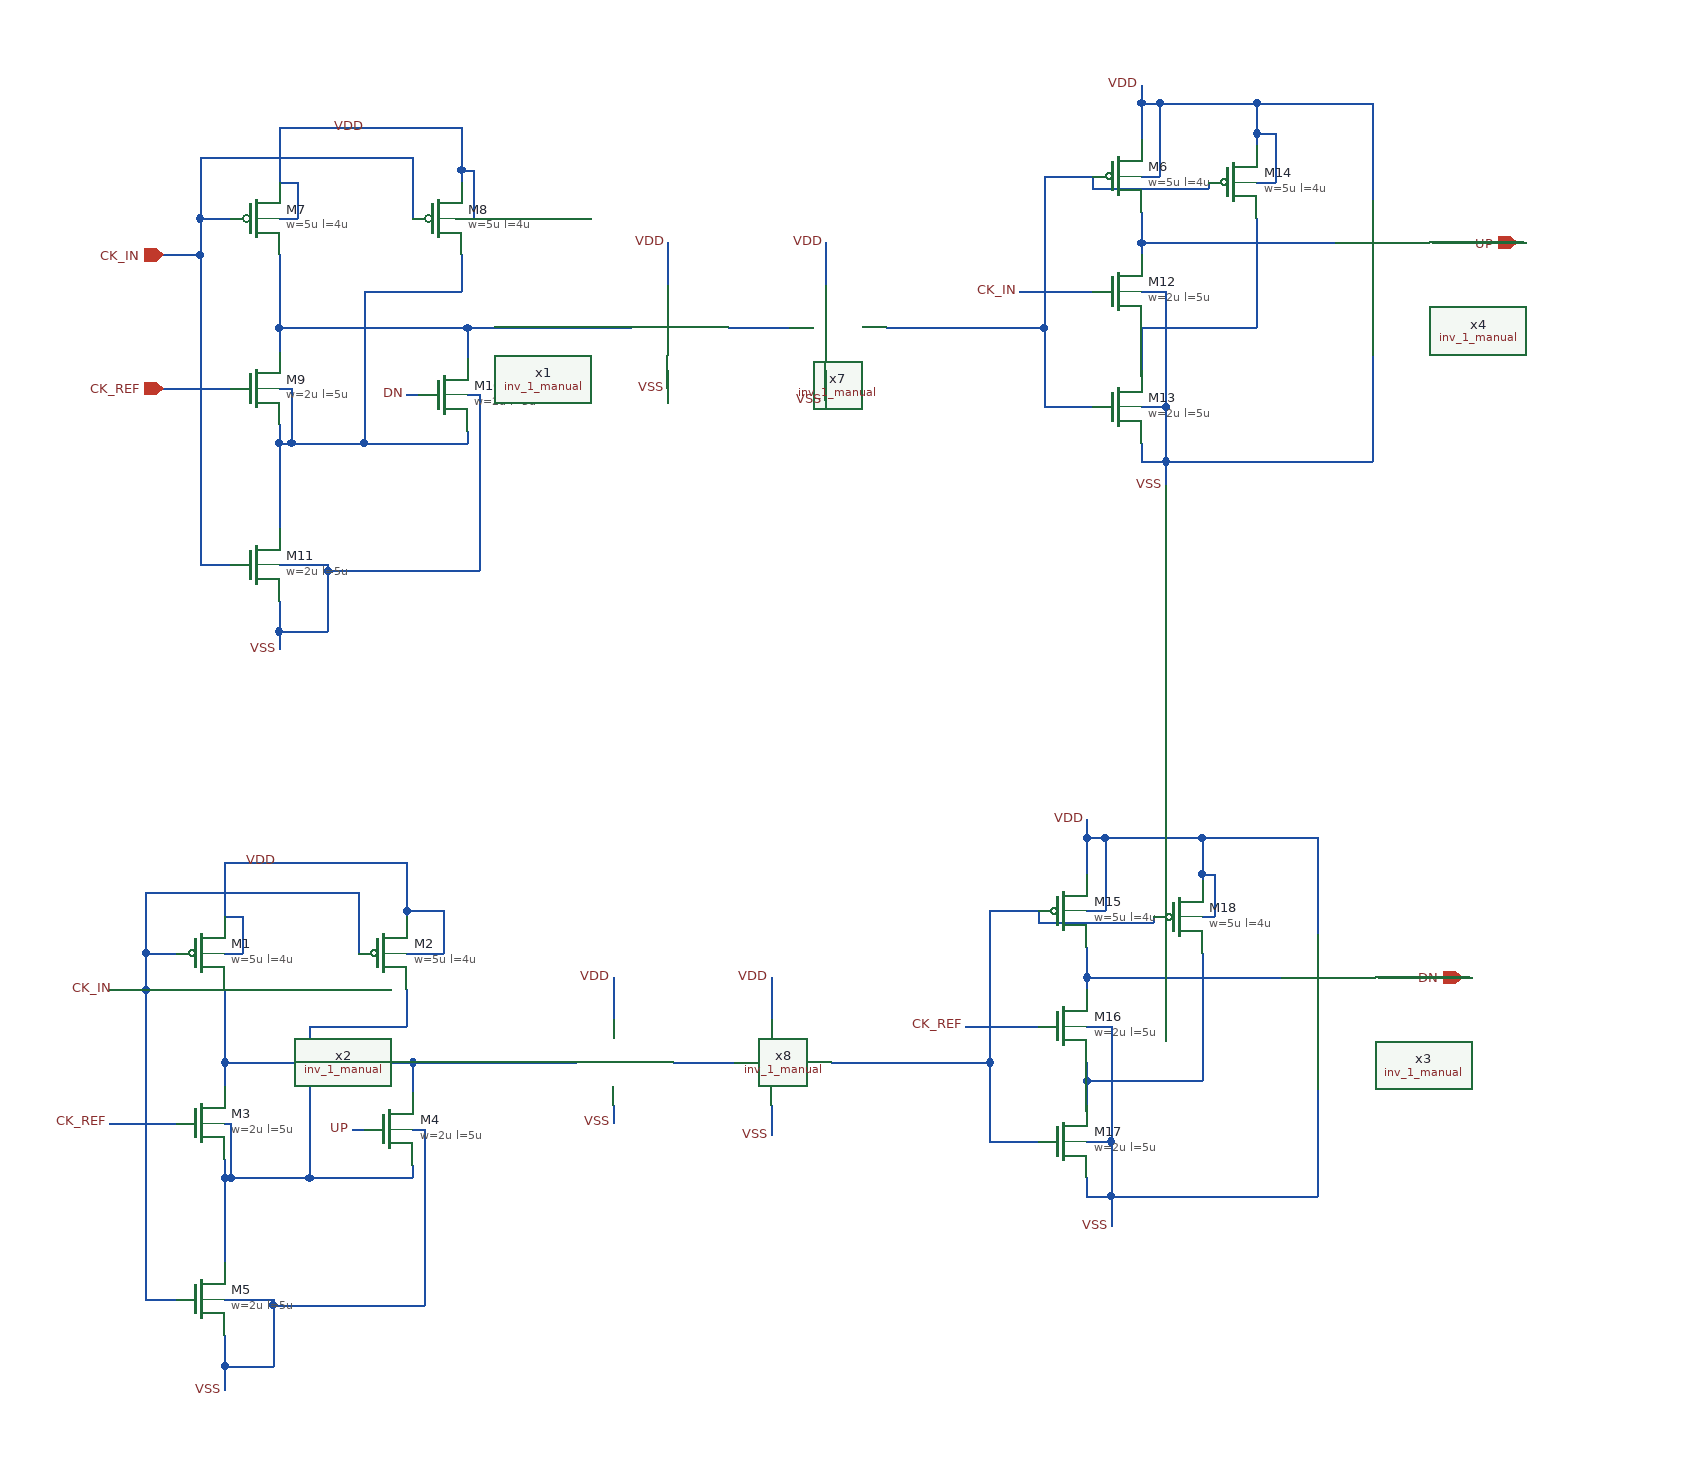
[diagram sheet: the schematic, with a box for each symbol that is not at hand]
v {xschem version=3.4.8RC file_version=1.2}
G {}
K {}
V {}
S {}
F {}
E {}
N 540 85 540 155 {lab=#net1}
N 695 75 695 85 {lab=#net1}
N 540 70 540 85 {lab=#net1}
N 540 -10 540 10 {lab=#net2}
N 695 -10 830 -10 {lab=#net2}
N 540 -70 540 -10 {lab=#net2}
N 695 -10 695 15 {lab=#net2}
N 540 -10 695 -10 {lab=#net2}
N 540 240 540 255 {lab=VSS}
N 475 185 500 185 {lab=CK_IN}
N 475 -70 475 185 {lab=CK_IN}
N 475 -100 500 -100 {lab=CK_IN}
N 445 40 500 40 {lab=CK_REF}
N 445 -70 475 -70 {lab=CK_IN}
N 475 -100 475 -70 {lab=CK_IN}
N 690 -70 690 -40 {lab=#net1}
N 610 85 695 85 {lab=#net1}
N 540 185 580 185 {lab=VSS}
N 580 190 580 240 {lab=VSS}
N 540 240 580 240 {lab=VSS}
N 540 215 540 240 {lab=VSS}
N 540 -175 540 -130 {lab=VDD}
N 540 -175 690 -175 {lab=VDD}
N 475 -150 475 -100 {lab=CK_IN}
N 475 -150 650 -150 {lab=CK_IN}
N 650 -150 650 -100 {lab=CK_IN}
N 690 -140 690 -130 {lab=VDD}
N 695 45 705 45 {lab=VSS}
N 705 45 705 190 {lab=VSS}
N 580 190 705 190 {lab=VSS}
N 580 185 580 190 {lab=VSS}
N 910 -10 960 -10 {lab=#net3}
N 990 -80 990 -45 {lab=VDD}
N 990 25 990 50 {lab=#net4}
N 860 25 860 40 {lab=#net5}
N 860 -80 860 -45 {lab=VDD}
N 1250 -135 1265 -135 {lab=VDD}
N 1210 -135 1210 -125 {lab=#net6}
N 1210 -125 1305 -125 {lab=#net6}
N 1305 -130 1305 -125 {lab=#net6}
N 1250 -195 1250 -165 {lab=VDD}
N 1265 -195 1345 -195 {lab=VDD}
N 1345 -170 1345 -160 {lab=VDD}
N 1265 -195 1265 -135 {lab=VDD}
N 1250 -195 1265 -195 {lab=VDD}
N 1250 -80 1250 -70 {lab=#net7}
N 1250 -10 1250 30 {lab=#net8}
N 1250 55 1270 55 {lab=#net9}
N 1270 55 1270 100 {lab=#net9}
N 1250 85 1250 100 {lab=#net9}
N 1170 -135 1210 -135 {lab=#net6}
N 1170 -10 1170 55 {lab=#net6}
N 1170 55 1210 55 {lab=#net6}
N 1040 -10 1170 -10 {lab=#net6}
N 1170 -135 1170 -10 {lab=#net6}
N 1250 -80 1410 -80 {lab=#net7}
N 1250 -105 1250 -80 {lab=#net7}
N 1250 -40 1270 -40 {lab=#net9}
N 1270 -40 1270 55 {lab=#net9}
N 1250 -210 1250 -195 {lab=VDD}
N 1250 100 1270 100 {lab=#net9}
N 1440 -195 1440 -115 {lab=VDD}
N 1345 -195 1440 -195 {lab=VDD}
N 1440 -45 1440 100 {lab=#net9}
N 1270 100 1440 100 {lab=#net9}
N 1150 -40 1210 -40 {lab=CK_IN}
N 1490 -80 1565 -80 {lab=UP}
N 540 -100 555 -100 {lab=VDD}
N 540 -130 555 -130 {lab=VDD}
N 555 -130 555 -100 {lab=VDD}
N 550 85 610 85 {lab=#net1}
N 610 -40 690 -40 {lab=#net1}
N 610 -40 610 85 {lab=#net1}
N 495 690 495 760 {lab=#net10}
N 650 680 650 690 {lab=#net10}
N 495 675 495 690 {lab=#net10}
N 495 595 495 615 {lab=#net11}
N 650 595 785 595 {lab=#net11}
N 495 535 495 595 {lab=#net11}
N 650 595 650 620 {lab=#net11}
N 495 595 650 595 {lab=#net11}
N 495 845 495 865 {lab=VSS}
N 430 790 455 790 {lab=CK_IN}
N 430 535 430 790 {lab=CK_IN}
N 430 505 455 505 {lab=CK_IN}
N 400 535 430 535 {lab=CK_IN}
N 430 505 430 535 {lab=CK_IN}
N 645 535 645 565 {lab=#net10}
N 565 690 650 690 {lab=#net10}
N 495 790 535 790 {lab=VSS}
N 535 795 535 845 {lab=VSS}
N 495 845 535 845 {lab=VSS}
N 495 820 495 845 {lab=VSS}
N 495 430 495 475 {lab=VDD}
N 495 430 645 430 {lab=VDD}
N 645 470 645 475 {lab=VDD}
N 430 455 430 505 {lab=CK_IN}
N 430 455 605 455 {lab=CK_IN}
N 605 455 605 505 {lab=CK_IN}
N 675 470 675 505 {lab=VDD}
N 645 470 675 470 {lab=VDD}
N 645 430 645 470 {lab=VDD}
N 650 650 660 650 {lab=VSS}
N 660 650 660 795 {lab=VSS}
N 535 795 660 795 {lab=VSS}
N 535 790 535 795 {lab=VSS}
N 865 595 915 595 {lab=#net12}
N 945 525 945 560 {lab=VDD}
N 945 630 945 655 {lab=VSS}
N 815 630 815 645 {lab=VSS}
N 815 525 815 560 {lab=VDD}
N 1205 470 1220 470 {lab=#net13}
N 1165 470 1165 480 {lab=#net14}
N 1165 480 1260 480 {lab=#net14}
N 1260 475 1260 480 {lab=#net14}
N 1205 410 1205 440 {lab=#net13}
N 1220 410 1300 410 {lab=#net13}
N 1300 440 1300 445 {lab=#net13}
N 1220 410 1220 470 {lab=#net13}
N 1205 410 1220 410 {lab=#net13}
N 1205 525 1205 535 {lab=#net15}
N 1205 610 1205 635 {lab=#net16}
N 1205 660 1225 660 {lab=VSS}
N 1225 660 1225 705 {lab=VSS}
N 1205 690 1205 705 {lab=VSS}
N 1125 470 1165 470 {lab=#net14}
N 1125 595 1125 660 {lab=#net14}
N 1125 660 1165 660 {lab=#net14}
N 995 595 1125 595 {lab=#net14}
N 1125 470 1125 595 {lab=#net14}
N 1205 525 1365 525 {lab=#net15}
N 1205 500 1205 525 {lab=#net15}
N 1205 565 1225 565 {lab=VSS}
N 1225 565 1225 660 {lab=VSS}
N 1205 395 1205 410 {lab=#net13}
N 1205 705 1225 705 {lab=VSS}
N 1395 410 1395 490 {lab=#net13}
N 1300 410 1395 410 {lab=#net13}
N 1395 560 1395 705 {lab=VSS}
N 1225 705 1395 705 {lab=VSS}
N 1105 565 1165 565 {lab=CK_REF}
N 1445 525 1520 525 {lab=DN}
N 495 505 510 505 {lab=VDD}
N 495 475 510 475 {lab=VDD}
N 510 475 510 505 {lab=VDD}
N 645 505 675 505 {lab=VDD}
N 500 690 565 690 {lab=#net10}
N 565 565 645 565 {lab=#net10}
N 565 565 565 690 {lab=#net10}
N 1250 -10 1345 -10 {lab=#net8}
N 1345 -100 1345 -10 {lab=#net8}
N 1300 475 1310 475 {lab=#net13}
N 1310 440 1310 475 {lab=#net13}
N 1300 440 1310 440 {lab=#net13}
N 1300 410 1300 440 {lab=#net13}
N 1205 610 1300 610 {lab=#net16}
N 1205 595 1205 610 {lab=#net16}
N 1300 505 1300 610 {lab=#net16}
N 400 645 455 645 {lab=CK_REF}
N 645 45 655 45 {lab=DN}
N 600 650 610 650 {lab=UP}
N 1345 -130 1360 -130 {lab=VDD}
N 1360 -170 1360 -130 {lab=VDD}
N 1345 -170 1360 -170 {lab=VDD}
N 1345 -195 1345 -170 {lab=VDD}
N 540 40 550 40 {lab=#net1}
N 550 40 550 85 {lab=#net1}
N 540 85 550 85 {lab=#net1}
N 495 645 500 645 {lab=#net10}
N 500 645 500 690 {lab=#net10}
N 495 690 500 690 {lab=#net10}
N 685 -100 700 -100 {lab=VDD}
N 700 -140 700 -100 {lab=VDD}
N 690 -140 700 -140 {lab=VDD}
N 690 -175 690 -140 {lab=VDD}
N 1225 705 1225 730 {lab=VSS}
N 1270 100 1270 120 {lab=#net9}
C {sg13g2_pr/sg13_lv_pmos.sym} 520 -100 0 0 {name=M7
l=4u
w=5u
ng=1
m=1
model=sg13_lv_pmos
spiceprefix=X
}
C {sg13g2_pr/sg13_lv_pmos.sym} 670 -100 0 0 {name=M8
l=4u
w=5u
ng=1
m=1
model=sg13_lv_pmos
spiceprefix=X
}
C {sg13g2_pr/sg13_lv_nmos.sym} 520 40 0 0 {name=M9
l=5u
w=2u
ng=5
m=1
model=sg13_lv_nmos
spiceprefix=X
}
C {sg13g2_pr/sg13_lv_nmos.sym} 675 45 0 0 {name=M10
l=5u
w=2u
ng=5
m=1
model=sg13_lv_nmos
spiceprefix=X
}
C {sg13g2_pr/sg13_lv_nmos.sym} 520 185 0 0 {name=M11
l=5u
w=2u
ng=5
m=1
model=sg13_lv_nmos
spiceprefix=X
}
C {devices/ipin.sym} 445 -70 0 0 {name=p6 lab=CK_IN
}
C {devices/ipin.sym} 445 40 0 0 {name=p7 lab=CK_REF
}
C {sg13g2_pr/sg13_lv_pmos.sym} 1230 -135 0 0 {name=M6
l=4u
w=5u
ng=1
m=1
model=sg13_lv_pmos
spiceprefix=X
}
C {sg13g2_pr/sg13_lv_nmos.sym} 1230 -40 0 0 {name=M12
l=5u
w=2u
ng=5
m=1
model=sg13_lv_nmos
spiceprefix=X
}
C {sg13g2_pr/sg13_lv_nmos.sym} 1230 55 0 0 {name=M13
l=5u
w=2u
ng=5
m=1
model=sg13_lv_nmos
spiceprefix=X
}
C {sg13g2_pr/sg13_lv_pmos.sym} 1325 -130 0 0 {name=M14
l=4u
w=5u
ng=1
m=1
model=sg13_lv_pmos
spiceprefix=X
}
C {devices/iopin.sym} 1560 -80 0 0 {name=p20 lab=UP}
C {lab_pin.sym} 645 45 0 0 {name=p5 sig_type=std_logic lab=DN}
C {sg13g2_pr/sg13_lv_pmos.sym} 475 505 0 0 {name=M1
l=4u
w=5u
ng=1
m=1
model=sg13_lv_pmos
spiceprefix=X
}
C {sg13g2_pr/sg13_lv_pmos.sym} 625 505 0 0 {name=M2
l=4u
w=5u
ng=1
m=1
model=sg13_lv_pmos
spiceprefix=X
}
C {sg13g2_pr/sg13_lv_nmos.sym} 475 645 0 0 {name=M3
l=5u
w=2u
ng=5
m=1
model=sg13_lv_nmos
spiceprefix=X
}
C {sg13g2_pr/sg13_lv_nmos.sym} 630 650 0 0 {name=M4
l=5u
w=2u
ng=5
m=1
model=sg13_lv_nmos
spiceprefix=X
}
C {sg13g2_pr/sg13_lv_nmos.sym} 475 790 0 0 {name=M5
l=5u
w=2u
ng=5
m=1
model=sg13_lv_nmos
spiceprefix=X
}
C {sg13g2_pr/sg13_lv_pmos.sym} 1185 470 0 0 {name=M15
l=4u
w=5u
ng=1
m=1
model=sg13_lv_pmos
spiceprefix=X
}
C {sg13g2_pr/sg13_lv_nmos.sym} 1185 565 0 0 {name=M16
l=5u
w=2u
ng=5
m=1
model=sg13_lv_nmos
spiceprefix=X
}
C {sg13g2_pr/sg13_lv_nmos.sym} 1185 660 0 0 {name=M17
l=5u
w=2u
ng=5
m=1
model=sg13_lv_nmos
spiceprefix=X
}
C {sg13g2_pr/sg13_lv_pmos.sym} 1280 475 0 0 {name=M18
l=4u
w=5u
ng=1
m=1
model=sg13_lv_pmos
spiceprefix=X
}
C {devices/iopin.sym} 1515 525 0 0 {name=p25 lab=DN}
C {lab_pin.sym} 600 650 0 0 {name=p26 sig_type=std_logic lab=UP}
C {lab_pin.sym} 405 535 0 0 {name=p10 sig_type=std_logic lab=CK_IN}
C {lab_pin.sym} 400 645 0 0 {name=p11 sig_type=std_logic lab=CK_REF}
C {lab_pin.sym} 1105 565 0 0 {name=p24 sig_type=std_logic lab=CK_REF}
C {lab_pin.sym} 1150 -40 0 0 {name=p19 sig_type=std_logic lab=CK_IN}
C {/foss/designs/DLL/others/inv_1_manual.sym} 860 -130 0 0 {name=x1}
C {/foss/designs/DLL/others/inv_1_manual.sym} 990 -130 0 0 {name=x7}
C {/foss/designs/DLL/others/inv_1_manual.sym} 815 475 0 0 {name=x2}
C {/foss/designs/DLL/others/inv_1_manual.sym} 945 475 0 0 {name=x8}
C {/foss/designs/DLL/others/inv_1_manual.sym} 1395 405 0 0 {name=x3}
C {/foss/designs/DLL/others/inv_1_manual.sym} 1440 -200 0 0 {name=x4}
C {devices/lab_pin.sym} 495 865 3 0 {name=p27 sig_type=std_logic lab=VSS}
C {devices/lab_pin.sym} 815 645 3 0 {name=p13 sig_type=std_logic lab=VSS}
C {devices/lab_pin.sym} 945 655 3 0 {name=p14 sig_type=std_logic lab=VSS}
C {devices/lab_pin.sym} 1225 730 3 0 {name=p15 sig_type=std_logic lab=VSS}
C {devices/lab_pin.sym} 540 255 3 0 {name=p1 sig_type=std_logic lab=VSS}
C {devices/lab_pin.sym} 859.2953824349504 40 3 0 {name=p9 sig_type=std_logic lab=VSS}
C {devices/lab_pin.sym} 989.2953824349504 50 3 0 {name=p2 sig_type=std_logic lab=VSS}
C {devices/lab_pin.sym} 1269.29538243495 120 3 0 {name=p17 sig_type=std_logic lab=VSS}
C {devices/lab_pin.sym} 612.5 -175 1 0 {name=p22 sig_type=std_logic lab=VDD}
C {devices/lab_pin.sym} 860 -80 1 0 {name=p3 sig_type=std_logic lab=VDD}
C {devices/lab_pin.sym} 990 -80 1 0 {name=p4 sig_type=std_logic lab=VDD}
C {devices/lab_pin.sym} 1250 -210 1 0 {name=p8 sig_type=std_logic lab=VDD}
C {devices/lab_pin.sym} 540 430 1 0 {name=p12 sig_type=std_logic lab=VDD}
C {devices/lab_pin.sym} 815 525 1 0 {name=p16 sig_type=std_logic lab=VDD}
C {devices/lab_pin.sym} 945 525 1 0 {name=p18 sig_type=std_logic lab=VDD}
C {devices/lab_pin.sym} 1205 395 1 0 {name=p21 sig_type=std_logic lab=VDD}
